One B-rep face of a CAD part: STEP entity #102.
In plain terms, the planar face has unit normal (1, 0, 0).
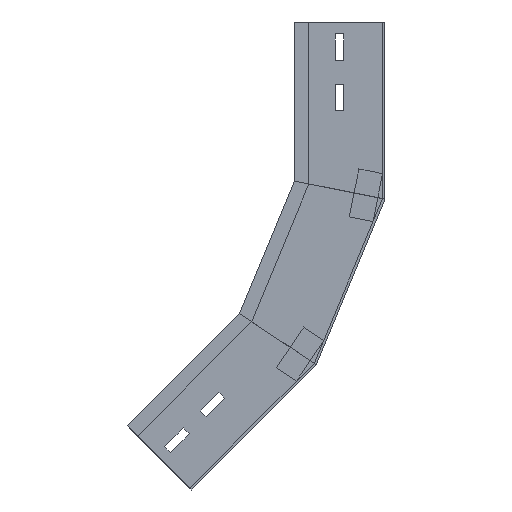
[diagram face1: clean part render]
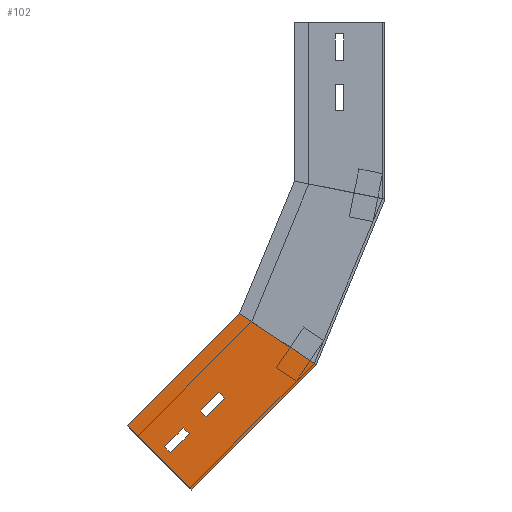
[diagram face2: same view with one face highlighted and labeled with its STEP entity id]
Its self-contained STEP definition (entity closure, numbers rounded to 3 decimals):
#3 = ORIENTED_EDGE ( 'NONE', *, *, #1419, .T. ) ;
#10 = LINE ( 'NONE', #32, #970 ) ;
#32 = CARTESIAN_POINT ( 'NONE',  ( 0., 41., -9.835 ) ) ;
#56 = LINE ( 'NONE', #866, #246 ) ;
#58 = ORIENTED_EDGE ( 'NONE', *, *, #1218, .F. ) ;
#60 = VERTEX_POINT ( 'NONE', #315 ) ;
#65 = VERTEX_POINT ( 'NONE', #1306 ) ;
#102 = ADVANCED_FACE ( 'NONE', ( #259, #376, #1193 ), #974, .F. ) ;
#103 = VECTOR ( 'NONE', #1376, 1000. ) ;
#151 = VECTOR ( 'NONE', #737, 1000. ) ;
#183 = LINE ( 'NONE', #733, #822 ) ;
#213 = LINE ( 'NONE', #670, #103 ) ;
#232 = VERTEX_POINT ( 'NONE', #1310 ) ;
#246 = VECTOR ( 'NONE', #1303, 1000. ) ;
#259 = FACE_BOUND ( 'NONE', #947, .T. ) ;
#268 = VECTOR ( 'NONE', #1088, 1000. ) ;
#280 = CARTESIAN_POINT ( 'NONE',  ( 0., 41., -73.505 ) ) ;
#285 = ORIENTED_EDGE ( 'NONE', *, *, #1277, .T. ) ;
#309 = ORIENTED_EDGE ( 'NONE', *, *, #1030, .F. ) ;
#315 = CARTESIAN_POINT ( 'NONE',  ( 0., 41., -31.835 ) ) ;
#331 = VERTEX_POINT ( 'NONE', #762 ) ;
#332 = CARTESIAN_POINT ( 'NONE',  ( 0., 41., -51.505 ) ) ;
#338 = DIRECTION ( 'NONE',  ( 0., 0., -1. ) ) ;
#355 = CARTESIAN_POINT ( 'NONE',  ( 0., 75., -131.682 ) ) ;
#368 = LINE ( 'NONE', #971, #1000 ) ;
#376 = FACE_OUTER_BOUND ( 'NONE', #944, .T. ) ;
#389 = VERTEX_POINT ( 'NONE', #403 ) ;
#391 = LINE ( 'NONE', #280, #151 ) ;
#403 = CARTESIAN_POINT ( 'NONE',  ( 0., 34., -51.505 ) ) ;
#406 = ORIENTED_EDGE ( 'NONE', *, *, #1293, .T. ) ;
#472 = LINE ( 'NONE', #1165, #748 ) ;
#483 = ORIENTED_EDGE ( 'NONE', *, *, #1007, .F. ) ;
#504 = VECTOR ( 'NONE', #338, 1000. ) ;
#523 = EDGE_CURVE ( 'NONE', #60, #961, #213, .T. ) ;
#576 = VERTEX_POINT ( 'NONE', #1283 ) ;
#622 = EDGE_CURVE ( 'NONE', #1116, #60, #10, .T. ) ;
#629 = CARTESIAN_POINT ( 'NONE',  ( 0., 0., 0. ) ) ;
#667 = LINE ( 'NONE', #1126, #798 ) ;
#670 = CARTESIAN_POINT ( 'NONE',  ( 0., 41., -31.835 ) ) ;
#677 = CARTESIAN_POINT ( 'NONE',  ( 0., 0., -146.6 ) ) ;
#683 = VERTEX_POINT ( 'NONE', #355 ) ;
#695 = DIRECTION ( 'NONE',  ( 0., 0., -1. ) ) ;
#729 = ORIENTED_EDGE ( 'NONE', *, *, #1155, .T. ) ;
#733 = CARTESIAN_POINT ( 'NONE',  ( 0., 34., -51.505 ) ) ;
#737 = DIRECTION ( 'NONE',  ( 0., -1., 0. ) ) ;
#748 = VECTOR ( 'NONE', #695, 1000. ) ;
#751 = EDGE_CURVE ( 'NONE', #576, #1116, #1460, .T. ) ;
#762 = CARTESIAN_POINT ( 'NONE',  ( 0., 0., 0. ) ) ;
#763 = DIRECTION ( 'NONE',  ( 0., 1., 0. ) ) ;
#772 = ORIENTED_EDGE ( 'NONE', *, *, #622, .T. ) ;
#798 = VECTOR ( 'NONE', #1028, 1000. ) ;
#806 = EDGE_CURVE ( 'NONE', #961, #576, #1442, .T. ) ;
#822 = VECTOR ( 'NONE', #965, 1000. ) ;
#854 = DIRECTION ( 'NONE',  ( 0., 1., 0. ) ) ;
#866 = CARTESIAN_POINT ( 'NONE',  ( 0., 28.051, -141.02 ) ) ;
#901 = VERTEX_POINT ( 'NONE', #1117 ) ;
#907 = CARTESIAN_POINT ( 'NONE',  ( 0., 41., -51.505 ) ) ;
#937 = VERTEX_POINT ( 'NONE', #1237 ) ;
#944 = EDGE_LOOP ( 'NONE', ( #309, #483, #729, #58 ) ) ;
#947 = EDGE_LOOP ( 'NONE', ( #3, #1045, #406, #285 ) ) ;
#961 = VERTEX_POINT ( 'NONE', #1017 ) ;
#965 = DIRECTION ( 'NONE',  ( 0., 0., 1. ) ) ;
#970 = VECTOR ( 'NONE', #1174, 1000. ) ;
#971 = CARTESIAN_POINT ( 'NONE',  ( 0., 0., 0. ) ) ;
#974 = PLANE ( 'NONE',  #1253 ) ;
#1000 = VECTOR ( 'NONE', #1093, 1000. ) ;
#1003 = LINE ( 'NONE', #907, #504 ) ;
#1007 = EDGE_CURVE ( 'NONE', #331, #65, #667, .T. ) ;
#1017 = CARTESIAN_POINT ( 'NONE',  ( 0., 34., -31.835 ) ) ;
#1028 = DIRECTION ( 'NONE',  ( 0., 1., 0. ) ) ;
#1030 = EDGE_CURVE ( 'NONE', #65, #683, #472, .T. ) ;
#1045 = ORIENTED_EDGE ( 'NONE', *, *, #1341, .T. ) ;
#1054 = CARTESIAN_POINT ( 'NONE',  ( 0., 41., -9.835 ) ) ;
#1088 = DIRECTION ( 'NONE',  ( 0., 0., 1. ) ) ;
#1093 = DIRECTION ( 'NONE',  ( 0., 0., -1. ) ) ;
#1101 = VECTOR ( 'NONE', #763, 1000. ) ;
#1116 = VERTEX_POINT ( 'NONE', #1054 ) ;
#1117 = CARTESIAN_POINT ( 'NONE',  ( 0., 41., -51.505 ) ) ;
#1126 = CARTESIAN_POINT ( 'NONE',  ( 0., 0., 0. ) ) ;
#1155 = EDGE_CURVE ( 'NONE', #331, #1355, #368, .T. ) ;
#1165 = CARTESIAN_POINT ( 'NONE',  ( 0., 75., 0. ) ) ;
#1174 = DIRECTION ( 'NONE',  ( 0., 0., -1. ) ) ;
#1193 = FACE_BOUND ( 'NONE', #1329, .T. ) ;
#1198 = DIRECTION ( 'NONE',  ( 0., 0., 1. ) ) ;
#1218 = EDGE_CURVE ( 'NONE', #683, #1355, #56, .T. ) ;
#1237 = CARTESIAN_POINT ( 'NONE',  ( 0., 41., -73.505 ) ) ;
#1253 = AXIS2_PLACEMENT_3D ( 'NONE', #629, #1435, #1198 ) ;
#1257 = VECTOR ( 'NONE', #854, 1000. ) ;
#1277 = EDGE_CURVE ( 'NONE', #232, #389, #183, .T. ) ;
#1283 = CARTESIAN_POINT ( 'NONE',  ( 0., 34., -9.835 ) ) ;
#1293 = EDGE_CURVE ( 'NONE', #937, #232, #391, .T. ) ;
#1303 = DIRECTION ( 'NONE',  ( 0., -0.981, -0.195 ) ) ;
#1306 = CARTESIAN_POINT ( 'NONE',  ( 0., 75., 0. ) ) ;
#1310 = CARTESIAN_POINT ( 'NONE',  ( 0., 34., -73.505 ) ) ;
#1326 = CARTESIAN_POINT ( 'NONE',  ( 0., 34., -9.835 ) ) ;
#1329 = EDGE_LOOP ( 'NONE', ( #1344, #772, #1465, #1378 ) ) ;
#1341 = EDGE_CURVE ( 'NONE', #901, #937, #1003, .T. ) ;
#1344 = ORIENTED_EDGE ( 'NONE', *, *, #751, .T. ) ;
#1355 = VERTEX_POINT ( 'NONE', #677 ) ;
#1376 = DIRECTION ( 'NONE',  ( 0., -1., 0. ) ) ;
#1378 = ORIENTED_EDGE ( 'NONE', *, *, #806, .T. ) ;
#1419 = EDGE_CURVE ( 'NONE', #389, #901, #1478, .T. ) ;
#1434 = CARTESIAN_POINT ( 'NONE',  ( 0., 41., -9.835 ) ) ;
#1435 = DIRECTION ( 'NONE',  ( -1., 0., 0. ) ) ;
#1442 = LINE ( 'NONE', #1326, #268 ) ;
#1460 = LINE ( 'NONE', #1434, #1257 ) ;
#1465 = ORIENTED_EDGE ( 'NONE', *, *, #523, .T. ) ;
#1478 = LINE ( 'NONE', #332, #1101 ) ;
